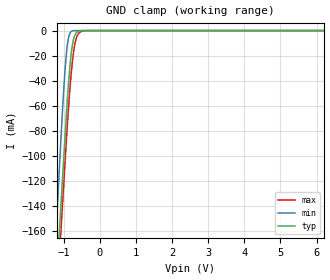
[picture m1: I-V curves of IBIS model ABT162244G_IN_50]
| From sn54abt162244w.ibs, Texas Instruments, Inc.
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| Model ABT162244G_IN
| Model ABT162244G_OE_IN
| Model ABT162244G_OUT
[Model]   ABT162244G_IN_50
Model_type  Input
Vinl=0.8
Vinh=2.0
| variable   typ   min   max
C_comp   3.29pF   2.71pF   4.82pF
[Temperature Range]   40   -40   100
| Ambient temperature   25   -40   85
[Voltage range]   5   4.5   5.5
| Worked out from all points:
|   GND clamp passes 1 mA (typ) near -0.62 V on its own axis
[GND Clamp]
| ABT162244G_IN_50
|   Voltage   I(typ)   I(min)   I(max)
-5V       -2.042A    -2.267A    -2.042A
-1.215V   -205.8mA   -162.5mA   -225.9mA
-1.13V    -164.6mA   -115.4mA   -185.2mA
-1.075V   -138mA     -84.96mA   -158.8mA
-950mV    -77.54mA   -26.26mA   -98.98mA
-875mV    -44.6mA    -6.649mA   -64.66mA
-800mV    -20.05mA   -969.2uA   -36.33mA
-750mV    -9.954mA   -188uA     -22.19mA
-700mV    -4.227mA   -21.87uA   -11.96mA
-625mV    -1.005mA   -611.1nA   -4.032mA
-400mV    -1.383uA   -44.34pA   -41.72uA
10V       16.83pA    5.182pA    1.079nA
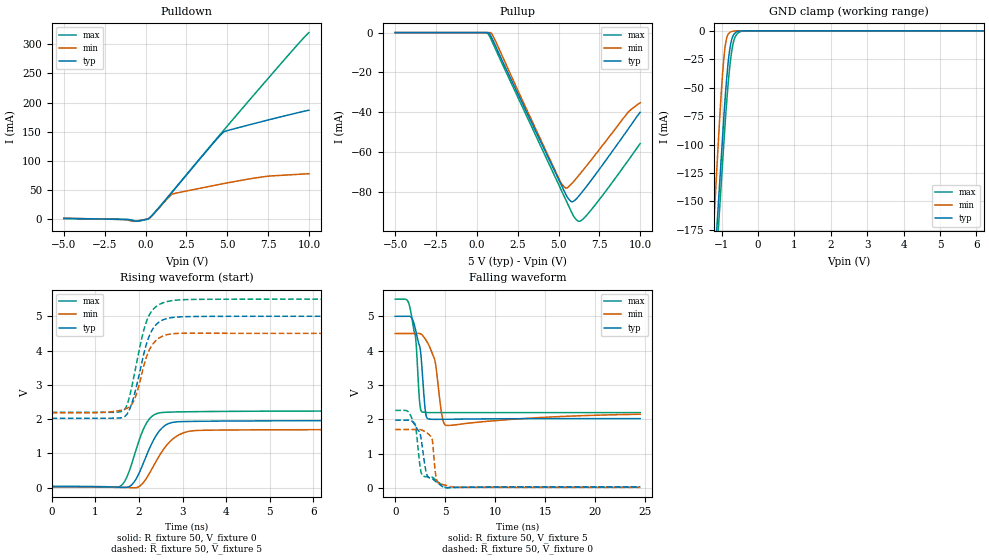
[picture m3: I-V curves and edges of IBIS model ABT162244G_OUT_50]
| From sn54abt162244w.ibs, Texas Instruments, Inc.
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[Model]   ABT162244G_OUT_50
Model_type  3-state
Enable   Active-Low
Vref =   0
Rref =   500
Cref =   50p
Vmeas =   1.5
| variable   typ   min   max
C_comp   4.34pF   3.34pF   6.51pF
| C_pullup   3.26pF   2.71pF   4.39pF
| C_pulldown   2.97pF   0.85pF   5.71pF
| C_tri-state   4.34pF   3.34pF   6.51pF
[Temperature Range]   40   -40   100
| Ambient temperature   25   -40   85
[Voltage range]   5   4.5   5.5
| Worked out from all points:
|   slope of the pulldown table from 0 to 0.75 V, typ, clamps not added: 41.8 ohm
|   slope of the pullup table from 0 to 0.75 V, typ, clamps not added: 1.85 kohm
|   GND clamp passes 1 mA (typ) near -0.59 V on its own axis
|   rising waveform, R_fixture 50, V_fixture 0: 20-80 % time 425ps typ, 517ps min, 365ps max; typ from 0.029 V to 1.97 V
|   falling waveform, R_fixture 50, V_fixture 5: 20-80 % time 706ps typ, 881ps min, 625ps max; typ from 5 V to 2.02 V
|   rising waveform, R_fixture 50, V_fixture 5: 20-80 % time 356ps typ, 328ps min, 349ps max; typ from 2.02 V to 5 V
|   falling waveform, R_fixture 50, V_fixture 0: 20-80 % time 644ps typ, 337ps min, 548ps max; typ from 1.98 V to 0.029 V
[GND Clamp]
| ABT162244G_OUT_50
|   Voltage   I(typ)   I(min)   I(max)
-5V       -2.142A    -2.36A     -2.144A
-1.23V    -224mA     -179.3mA   -245.3mA
-1.2V     -208.8mA   -162mA     -230.3mA
-1.135V   -175.8mA   -124.5mA   -197.6mA
-1.075V   -145.4mA   -90mA      -167.6mA
-1V       -107.5mA   -50.53mA   -130mA
-925mV    -70.08mA   -20.21mA   -92.54mA
-825mV    -29.71mA   -3.318mA   -48.67mA
-725mV    -8.075mA   -672.7uA   -18.7mA
-600mV    -1.212mA   -31.37uA   -3.83mA
-370mV    -2.194uA   -675pA     -62.93uA
10V       30.75pA    19.07pA    1.517nA
[Pulldown]
| ABT162244G_OUT_50
|   Voltage   I(typ)   I(min)   I(max)
-5V       1.257mA    1.331mA    852uA
-1.285V   -685.5uA   -871.1uA   -525.5uA
-670mV    -3.385mA   -3.807mA   -2.834mA
-360mV    -2.767mA   -2.429mA   -3.149mA
205mV     1.191mA    1.018mA    1.508mA
590mV     12.06mA    11.71mA    12.53mA
1.385V    38.2mA     36.63mA    38.74mA
1.635V    46.57mA    42.9mA     47.14mA
4.08V     128.2mA    57.1mA     129.2mA
4.8V      149.7mA    61.02mA    153.1mA
7.415V    169.5mA    73.35mA    238.7mA
10V       187mA      77.89mA    320.2mA
[Pullup]
| ABT162244G_OUT_50
|   Voltage   I(typ)   I(min)   I(max)
-5V       0A         0A         0A
660mV     -27.36uA   -12.72nA   -444.4uA
870mV     -1.988mA   -234.5uA   -3.464mA
1.055V    -5.146mA   -2.827mA   -6.746mA
5.125V    -75.7mA    -74.99mA   -78.3mA
5.45V     -81.26mA   -78.01mA   -84mA
5.8V      -84.82mA   -75.8mA    -90.12mA
6.2V      -82.39mA   -72.01mA   -94.53mA
6.555V    -78.83mA   -68.45mA   -93.08mA
7.61V     -67.3mA    -57.49mA   -82.56mA
9.22V     -48.89mA   -40.36mA   -64.62mA
10V       -39.96mA   -35.22mA   -55.64mA
[Ramp]
| ABT162244G_OUT_50
| variable   typ   min   max
dV/dt_r   1.18/4.31E-10   1.03/5.27E-10   1.35/3.73E-10
dV/dt_f   1.80/7.10E-10   1.61/9.08E-10   1.98/6.28E-10
R_load = 50
[Rising Waveform]
| ABT162244G_OUT_50
R_fixture =   50
C_fixture =   0
L_fixture =   0
V_fixture =   0
V_fixture_min = 0
V_fixture_max = 0
|   Time   V(typ)   V(min)   V(max)
0s        28.89mV    20.65mV    36.95mV
1.59ns    7.437mV    4.088mV    55.17mV
1.72ns    8.194mV    4.567mV    297.1mV
1.87ns    130.5mV    -8.35mV    837.5mV
2.18ns    956.9mV    286.8mV    1.894V
2.395ns   1.519V     767.5mV    2.151V
2.6ns     1.814V     1.177V     2.197V
2.985ns   1.925V     1.579V     2.21V
3.515ns   1.936V     1.673V     2.219V
24.54ns   1.969V     1.701V     2.253V
[Falling Waveform]
| ABT162244G_OUT_50
R_fixture =   50
C_fixture =   0
L_fixture =   0
V_fixture =   5
V_fixture_min = 4.5
V_fixture_max = 5.5
|   Time   V(typ)   V(min)   V(max)
0s        5V         4.5V       5.5V
1.45ns    5.002V     4.5V       5.282V
2.04ns    4.605V     4.502V     4.375V
2.425ns   4.151V     4.5V       2.566V
2.68ns    3.488V     4.461V     2.215V
3.145ns   2.061V     4.276V     2.2V
3.97ns    1.999V     3.718V     2.197V
4.66ns    2.002V     2.147V     2.197V
5.06ns    2.003V     1.829V     2.197V
24.54ns   2.022V     2.15V      2.196V
[Rising Waveform]
| ABT162244G_OUT_50
R_fixture =   50
C_fixture =   0
L_fixture =   0
V_fixture =   5
V_fixture_min = 4.5
V_fixture_max = 5.5
|   Time   V(typ)   V(min)   V(max)
0s        2.022V     2.183V     2.196V
1.655ns   2.054V     2.275V     2.254V
1.765ns   2.228V     2.341V     2.565V
1.9ns     2.732V     2.585V     3.334V
2.085ns   3.752V     3.418V     4.46V
2.22ns    4.367V     3.964V     4.994V
2.325ns   4.642V     4.198V     5.2V
2.455ns   4.823V     4.359V     5.334V
2.835ns   4.973V     4.496V     5.468V
24.54ns   5V         4.5V       5.5V
[Falling Waveform]
| ABT162244G_OUT_50
R_fixture =   50
C_fixture =   0
L_fixture =   0
V_fixture =   0
V_fixture_min = 0
V_fixture_max = 0
|   Time   V(typ)   V(min)   V(max)
0s        1.976V     1.705V     2.261V
1.19ns    1.977V     1.705V     2.249V
1.98ns    1.832V     1.706V     1.863V
2.44ns    1.633V     1.705V     734.2mV
3.08ns    485.3mV    1.624V     330.5mV
3.435ns   294.9mV    1.544V     324.1mV
3.71ns    273.2mV    1.401V     316.2mV
4.165ns   164.6mV    225.5mV    205.5mV
5.075ns   5.838mV    82.51mV    16.56mV
24.54ns   28.89mV    20.65mV    36.95mV
